One B-rep face of a CAD part: STEP entity #1141.
In plain terms, the planar face has unit normal (-1, 0, 0).
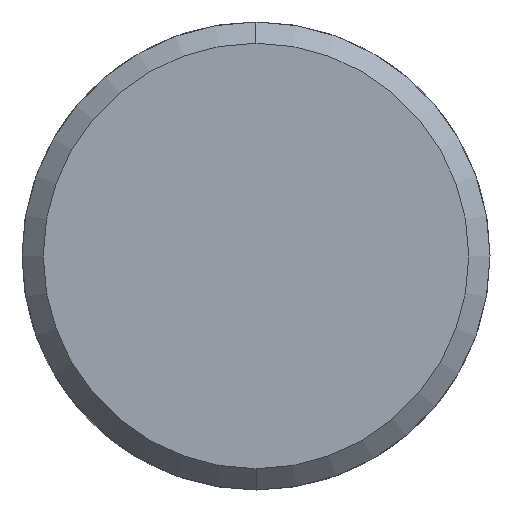
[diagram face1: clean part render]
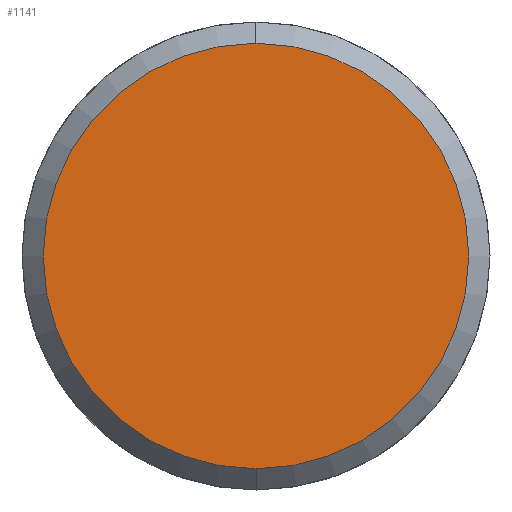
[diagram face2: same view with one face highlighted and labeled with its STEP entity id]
Its self-contained STEP definition (entity closure, numbers rounded to 3 decimals):
#1073=CARTESIAN_POINT('Vertex',(-5.,0.,-10.)) ;
#1076=CARTESIAN_POINT('Axis2P3D Location',(-5.,0.,0.)) ;
#1080=CARTESIAN_POINT('Vertex',(-5.,10.,0.)) ;
#1083=CARTESIAN_POINT('Axis2P3D Location',(-5.,0.,0.)) ;
#1087=CARTESIAN_POINT('Vertex',(-5.,0.,10.)) ;
#1109=CARTESIAN_POINT('Axis2P3D Location',(-5.,0.,0.)) ;
#1113=CARTESIAN_POINT('Vertex',(-5.,-10.,0.)) ;
#1116=CARTESIAN_POINT('Axis2P3D Location',(-5.,0.,0.)) ;
#1130=CARTESIAN_POINT('Axis2P3D Location',(-5.,0.,0.)) ;
#1077=DIRECTION('Axis2P3D Direction',(1.,0.,-0.)) ;
#1084=DIRECTION('Axis2P3D Direction',(1.,0.,-0.)) ;
#1110=DIRECTION('Axis2P3D Direction',(1.,0.,-0.)) ;
#1117=DIRECTION('Axis2P3D Direction',(1.,0.,-0.)) ;
#1131=DIRECTION('Axis2P3D Direction',(1.,0.,-0.)) ;
#1132=DIRECTION('Axis2P3D XDirection',(-0.,0.,-1.)) ;
#1078=AXIS2_PLACEMENT_3D('Circle Axis2P3D',#1076,#1077,$) ;
#1085=AXIS2_PLACEMENT_3D('Circle Axis2P3D',#1083,#1084,$) ;
#1111=AXIS2_PLACEMENT_3D('Circle Axis2P3D',#1109,#1110,$) ;
#1118=AXIS2_PLACEMENT_3D('Circle Axis2P3D',#1116,#1117,$) ;
#1133=AXIS2_PLACEMENT_3D('Plane Axis2P3D',#1130,#1131,#1132) ;
#1136=ORIENTED_EDGE('',*,*,#1082,.F.) ;
#1137=ORIENTED_EDGE('',*,*,#1120,.F.) ;
#1138=ORIENTED_EDGE('',*,*,#1115,.F.) ;
#1139=ORIENTED_EDGE('',*,*,#1089,.F.) ;
#1141=ADVANCED_FACE('351-12X56X100',(#1140),#1134,.F.) ;
#1079=CIRCLE('generated circle',#1078,10.) ;
#1086=CIRCLE('generated circle',#1085,10.) ;
#1112=CIRCLE('generated circle',#1111,10.) ;
#1119=CIRCLE('generated circle',#1118,10.) ;
#1082=EDGE_CURVE('',#1074,#1081,#1079,.T.) ;
#1089=EDGE_CURVE('',#1081,#1088,#1086,.T.) ;
#1115=EDGE_CURVE('',#1088,#1114,#1112,.T.) ;
#1120=EDGE_CURVE('',#1114,#1074,#1119,.T.) ;
#1135=EDGE_LOOP('',(#1136,#1137,#1138,#1139)) ;
#1140=FACE_OUTER_BOUND('',#1135,.T.) ;
#1134=PLANE('Plane',#1133) ;
#1074=VERTEX_POINT('',#1073) ;
#1081=VERTEX_POINT('',#1080) ;
#1088=VERTEX_POINT('',#1087) ;
#1114=VERTEX_POINT('',#1113) ;
